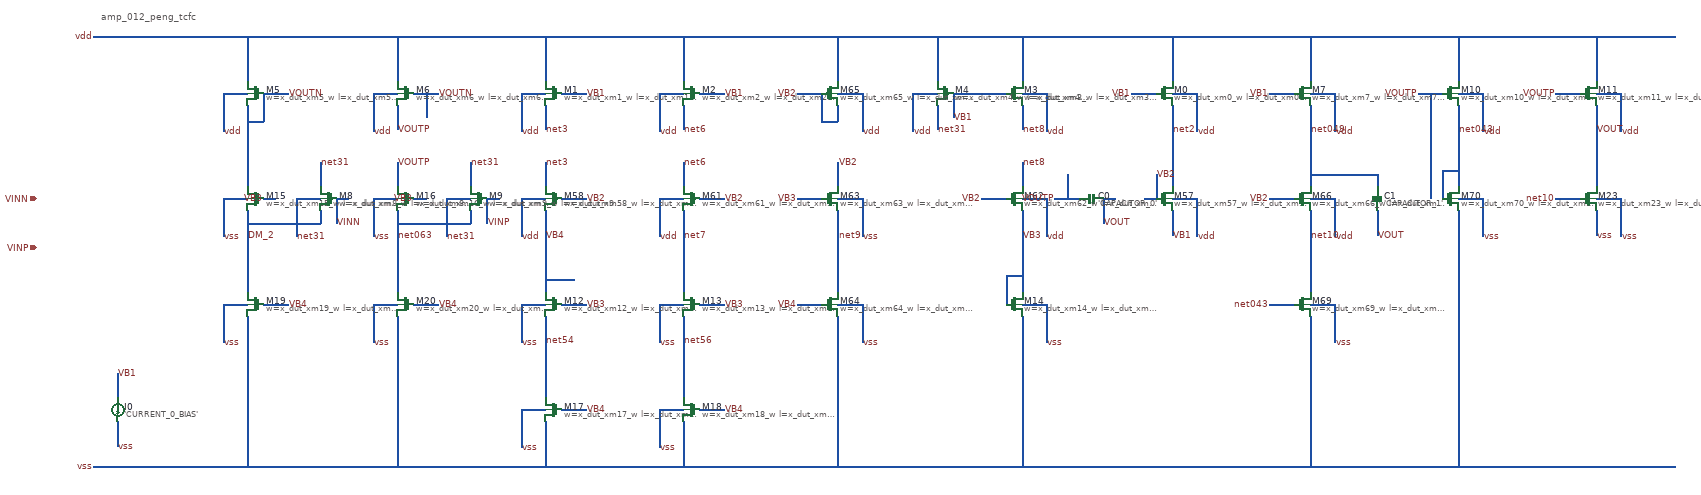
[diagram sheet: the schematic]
v {xschem version=3.4.6 file_version=1.2}
G {}
K {}
V {}
S {}
E {}
T {amp_012_peng_tcfc} -1910 -200 0 0 0.4 0.4 {}
C {devices/capa_np.sym} 530 260 1 0 {name=C0 value='CAPACITOR_0'}
C {devices/capa_np.sym} 1235 260 0 0 {name=C1 value='CAPACITOR_1'}
C {devices/isource_np.sym} -1870 780 0 0 {name=I0 value='CURRENT_0_BIAS'}
C {devices/sg13_lv_pmos_np.sym} 710 0 0 0 {name=M0 model=sg13_lv_pmos spiceprefix=X w=x_dut_xm0_w l=x_dut_xm0_l m=x_dut_xm0_m}
C {devices/sg13_lv_pmos_np.sym} -795 0 0 1 {name=M1 model=sg13_lv_pmos spiceprefix=X w=x_dut_xm1_w l=x_dut_xm1_l m=x_dut_xm1_m}
C {devices/sg13_lv_pmos_np.sym} 1415 0 0 0 {name=M10 model=sg13_lv_pmos spiceprefix=X w=x_dut_xm10_w l=x_dut_xm10_l m=x_dut_xm10_m}
C {devices/sg13_lv_pmos_np.sym} 1755 0 0 0 {name=M11 model=sg13_lv_pmos spiceprefix=X w=x_dut_xm11_w l=x_dut_xm11_l m=x_dut_xm11_m}
C {devices/sg13_lv_nmos_np.sym} -795 520 0 1 {name=M12 model=sg13_lv_nmos spiceprefix=X w=x_dut_xm12_w l=x_dut_xm12_l m=x_dut_xm12_m}
C {devices/sg13_lv_nmos_np.sym} -455 520 0 1 {name=M13 model=sg13_lv_nmos spiceprefix=X w=x_dut_xm13_w l=x_dut_xm13_l m=x_dut_xm13_m}
C {devices/sg13_lv_nmos_np.sym} 340 520 0 0 {name=M14 model=sg13_lv_nmos spiceprefix=X w=x_dut_xm14_w l=x_dut_xm14_l m=x_dut_xm14_m}
C {devices/sg13_lv_nmos_np.sym} -1530 260 0 1 {name=M15 model=sg13_lv_nmos spiceprefix=X w=x_dut_xm15_w l=x_dut_xm15_l m=x_dut_xm15_m}
C {devices/sg13_lv_nmos_np.sym} -1160 260 0 1 {name=M16 model=sg13_lv_nmos spiceprefix=X w=x_dut_xm16_w l=x_dut_xm16_l m=x_dut_xm16_m}
C {devices/sg13_lv_nmos_np.sym} -795 780 0 1 {name=M17 model=sg13_lv_nmos spiceprefix=X w=x_dut_xm17_w l=x_dut_xm17_l m=x_dut_xm17_m}
C {devices/sg13_lv_nmos_np.sym} -455 780 0 1 {name=M18 model=sg13_lv_nmos spiceprefix=X w=x_dut_xm18_w l=x_dut_xm18_l m=x_dut_xm18_m}
C {devices/sg13_lv_nmos_np.sym} -1530 520 0 1 {name=M19 model=sg13_lv_nmos spiceprefix=X w=x_dut_xm19_w l=x_dut_xm19_l m=x_dut_xm19_m}
C {devices/sg13_lv_pmos_np.sym} -455 0 0 1 {name=M2 model=sg13_lv_pmos spiceprefix=X w=x_dut_xm2_w l=x_dut_xm2_l m=x_dut_xm2_m}
C {devices/sg13_lv_nmos_np.sym} -1160 520 0 1 {name=M20 model=sg13_lv_nmos spiceprefix=X w=x_dut_xm20_w l=x_dut_xm20_l m=x_dut_xm20_m}
C {devices/sg13_lv_nmos_np.sym} 1755 260 0 0 {name=M23 model=sg13_lv_nmos spiceprefix=X w=x_dut_xm23_w l=x_dut_xm23_l m=x_dut_xm23_m}
C {devices/sg13_lv_pmos_np.sym} 340 0 0 0 {name=M3 model=sg13_lv_pmos spiceprefix=X w=x_dut_xm3_w l=x_dut_xm3_l m=x_dut_xm3_m}
C {devices/sg13_lv_pmos_np.sym} 170 0 0 1 {name=M4 model=sg13_lv_pmos spiceprefix=X w=x_dut_xm4_w l=x_dut_xm4_l m=x_dut_xm4_m}
C {devices/sg13_lv_pmos_np.sym} -1530 0 0 1 {name=M5 model=sg13_lv_pmos spiceprefix=X w=x_dut_xm5_w l=x_dut_xm5_l m=x_dut_xm5_m}
C {devices/sg13_lv_pmos_np.sym} 710 260 0 0 {name=M57 model=sg13_lv_pmos spiceprefix=X w=x_dut_xm57_w l=x_dut_xm57_l m=x_dut_xm57_m}
C {devices/sg13_lv_pmos_np.sym} -795 260 0 1 {name=M58 model=sg13_lv_pmos spiceprefix=X w=x_dut_xm58_w l=x_dut_xm58_l m=x_dut_xm58_m}
C {devices/sg13_lv_pmos_np.sym} -1160 0 0 1 {name=M6 model=sg13_lv_pmos spiceprefix=X w=x_dut_xm6_w l=x_dut_xm6_l m=x_dut_xm6_m}
C {devices/sg13_lv_pmos_np.sym} -455 260 0 1 {name=M61 model=sg13_lv_pmos spiceprefix=X w=x_dut_xm61_w l=x_dut_xm61_l m=x_dut_xm61_m}
C {devices/sg13_lv_pmos_np.sym} 340 260 0 0 {name=M62 model=sg13_lv_pmos spiceprefix=X w=x_dut_xm62_w l=x_dut_xm62_l m=x_dut_xm62_m}
C {devices/sg13_lv_nmos_np.sym} -115 260 0 0 {name=M63 model=sg13_lv_nmos spiceprefix=X w=x_dut_xm63_w l=x_dut_xm63_l m=x_dut_xm63_m}
C {devices/sg13_lv_nmos_np.sym} -115 520 0 0 {name=M64 model=sg13_lv_nmos spiceprefix=X w=x_dut_xm64_w l=x_dut_xm64_l m=x_dut_xm64_m}
C {devices/sg13_lv_pmos_np.sym} -115 0 0 0 {name=M65 model=sg13_lv_pmos spiceprefix=X w=x_dut_xm65_w l=x_dut_xm65_l m=x_dut_xm65_m}
C {devices/sg13_lv_pmos_np.sym} 1050 260 0 0 {name=M66 model=sg13_lv_pmos spiceprefix=X w=x_dut_xm66_w l=x_dut_xm66_l m=x_dut_xm66_m}
C {devices/sg13_lv_nmos_np.sym} 1050 520 0 0 {name=M69 model=sg13_lv_nmos spiceprefix=X w=x_dut_xm69_w l=x_dut_xm69_l m=x_dut_xm69_m}
C {devices/sg13_lv_pmos_np.sym} 1050 0 0 0 {name=M7 model=sg13_lv_pmos spiceprefix=X w=x_dut_xm7_w l=x_dut_xm7_l m=x_dut_xm7_m}
C {devices/sg13_lv_nmos_np.sym} 1415 260 0 0 {name=M70 model=sg13_lv_nmos spiceprefix=X w=x_dut_xm70_w l=x_dut_xm70_l m=x_dut_xm70_m}
C {devices/sg13_lv_pmos_np.sym} -1350 260 0 1 {name=M8 model=sg13_lv_pmos spiceprefix=X w=x_dut_xm8_w l=x_dut_xm8_l m=x_dut_xm8_m}
C {devices/sg13_lv_pmos_np.sym} -980 260 0 1 {name=M9 model=sg13_lv_pmos spiceprefix=X w=x_dut_xm9_w l=x_dut_xm9_l m=x_dut_xm9_m}
N -1870 690 -1870 750 {}
N -1870 810 -1870 870 {}
N -1610 0 -1610 94 {}
N -1610 260 -1610 354 {}
N -1610 520 -1610 614 {}
N -1550 -140 -1550 -30 {}
N -1550 30 -1550 230 {}
N -1550 290 -1550 490 {}
N -1550 550 -1550 920 {}
N -1510 0 -1510 70 {}
N -1430 260 -1430 354 {}
N -1370 170 -1370 230 {}
N -1370 290 -1370 320 {}
N -1330 260 -1330 320 {}
N -1240 0 -1240 94 {}
N -1240 260 -1240 354 {}
N -1240 520 -1240 614 {}
N -1180 -140 -1180 -30 {}
N -1180 30 -1180 90 {}
N -1180 170 -1180 230 {}
N -1180 290 -1180 490 {}
N -1180 550 -1180 920 {}
N -1110 0 -1110 60 {}
N -1060 260 -1060 354 {}
N -1000 170 -1000 230 {}
N -1000 290 -1000 320 {}
N -960 260 -960 320 {}
N -875 0 -875 94 {}
N -875 260 -875 354 {}
N -875 520 -875 614 {}
N -875 780 -875 874 {}
N -815 -140 -815 -30 {}
N -815 30 -815 90 {}
N -815 170 -815 230 {}
N -815 290 -815 490 {}
N -815 550 -815 750 {}
N -815 810 -815 920 {}
N -535 0 -535 94 {}
N -535 260 -535 354 {}
N -535 520 -535 614 {}
N -535 780 -535 874 {}
N -475 -140 -475 -30 {}
N -475 30 -475 90 {}
N -475 170 -475 230 {}
N -475 290 -475 490 {}
N -475 550 -475 750 {}
N -475 810 -475 920 {}
N -135 0 -135 70 {}
N -95 -140 -95 -30 {}
N -95 30 -95 70 {}
N -95 170 -95 230 {}
N -95 290 -95 490 {}
N -95 550 -95 920 {}
N -35 0 -35 94 {}
N -35 260 -35 354 {}
N -35 520 -35 614 {}
N 90 0 90 94 {}
N 150 -140 150 -30 {}
N 150 30 150 90 {}
N 190 0 190 60 {}
N 320 450 320 520 {}
N 360 -140 360 -30 {}
N 360 30 360 90 {}
N 360 170 360 230 {}
N 360 290 360 490 {}
N 360 550 360 920 {}
N 420 0 420 94 {}
N 420 260 420 354 {}
N 420 520 420 614 {}
N 470 200 470 260 {}
N 560 260 560 320 {}
N 690 200 690 260 {}
N 730 -140 730 -30 {}
N 730 30 730 230 {}
N 730 290 730 350 {}
N 790 0 790 94 {}
N 790 260 790 354 {}
N 1070 -140 1070 -30 {}
N 1070 30 1070 230 {}
N 1070 290 1070 490 {}
N 1070 550 1070 920 {}
N 1130 0 1130 94 {}
N 1130 260 1130 354 {}
N 1130 520 1130 614 {}
N 1235 200 1235 230 {}
N 1235 290 1235 350 {}
N 1365 0 1365 260 {}
N 1395 190 1395 260 {}
N 1435 -140 1435 -30 {}
N 1435 30 1435 230 {}
N 1435 290 1435 920 {}
N 1495 0 1495 94 {}
N 1495 260 1495 354 {}
N 1775 -140 1775 -30 {}
N 1775 30 1775 230 {}
N 1775 290 1775 350 {}
N 1835 0 1835 94 {}
N 1835 260 1835 354 {}
N -1930 -140 1970 -140 {}
N -1610 0 -1550 0 {}
N -1510 0 -1450 0 {}
N -1240 0 -1180 0 {}
N -1140 0 -1080 0 {}
N -875 0 -815 0 {}
N -775 0 -715 0 {}
N -535 0 -475 0 {}
N -435 0 -375 0 {}
N -195 0 -135 0 {}
N -95 0 -35 0 {}
N 90 0 150 0 {}
N 190 0 320 0 {}
N 360 0 420 0 {}
N 630 0 690 0 {}
N 730 0 790 0 {}
N 970 0 1030 0 {}
N 1070 0 1130 0 {}
N 1335 0 1395 0 {}
N 1435 0 1495 0 {}
N 1675 0 1735 0 {}
N 1775 0 1835 0 {}
N -1550 70 -1510 70 {}
N -135 70 -95 70 {}
N 1395 190 1435 190 {}
N 1070 200 1235 200 {}
N -1610 260 -1550 260 {}
N -1510 260 -1480 260 {}
N -1430 260 -1370 260 {}
N -1330 260 -1300 260 {}
N -1240 260 -1180 260 {}
N -1140 260 -1110 260 {}
N -1060 260 -1000 260 {}
N -960 260 -930 260 {}
N -875 260 -815 260 {}
N -775 260 -715 260 {}
N -535 260 -475 260 {}
N -435 260 -375 260 {}
N -195 260 -135 260 {}
N -95 260 -35 260 {}
N 260 260 320 260 {}
N 360 260 420 260 {}
N 440 260 500 260 {}
N 560 260 590 260 {}
N 660 260 690 260 {}
N 730 260 790 260 {}
N 970 260 1030 260 {}
N 1070 260 1130 260 {}
N 1435 260 1495 260 {}
N 1675 260 1735 260 {}
N 1775 260 1835 260 {}
N -1550 320 -1370 320 {}
N -1180 320 -1000 320 {}
N 320 450 360 450 {}
N -815 460 -745 460 {}
N -1610 520 -1550 520 {}
N -1510 520 -1450 520 {}
N -1240 520 -1180 520 {}
N -1140 520 -1080 520 {}
N -875 520 -815 520 {}
N -775 520 -715 520 {}
N -535 520 -475 520 {}
N -435 520 -375 520 {}
N -195 520 -135 520 {}
N -95 520 -35 520 {}
N 360 520 420 520 {}
N 970 520 1030 520 {}
N 1070 520 1130 520 {}
N -875 780 -815 780 {}
N -775 780 -715 780 {}
N -535 780 -475 780 {}
N -435 780 -375 780 {}
N -1930 920 1970 920 {}
C {devices/lab_wire.sym} -1930 -140 0 0 {name=l0 lab=vdd}
C {devices/lab_wire.sym} -1930 920 0 0 {name=l1 lab=vss}
C {devices/lab_wire.sym} -1550 350 2 0 {name=l2 lab=DM_2}
C {devices/lab_wire.sym} -715 0 0 1 {name=l3 lab=VB1}
C {devices/lab_wire.sym} -375 0 0 1 {name=l4 lab=VB1}
C {devices/lab_wire.sym} 190 60 2 0 {name=l5 lab=VB1}
C {devices/lab_wire.sym} 630 0 0 0 {name=l6 lab=VB1}
C {devices/lab_wire.sym} 730 350 2 0 {name=l7 lab=VB1}
C {devices/lab_wire.sym} 970 0 0 0 {name=l8 lab=VB1}
C {devices/lab_wire.sym} -715 260 0 1 {name=l9 lab=VB2}
C {devices/lab_wire.sym} -375 260 0 1 {name=l10 lab=VB2}
C {devices/lab_wire.sym} -195 0 0 0 {name=l11 lab=VB2}
C {devices/lab_wire.sym} -95 170 0 1 {name=l12 lab=VB2}
C {devices/lab_wire.sym} 260 260 0 0 {name=l13 lab=VB2}
C {devices/lab_wire.sym} 690 200 0 1 {name=l14 lab=VB2}
C {devices/lab_wire.sym} 970 260 0 0 {name=l15 lab=VB2}
C {devices/lab_wire.sym} -1510 260 0 0 {name=l16 lab=VB3}
C {devices/lab_wire.sym} -1140 260 0 0 {name=l17 lab=VB3}
C {devices/lab_wire.sym} -715 520 0 1 {name=l18 lab=VB3}
C {devices/lab_wire.sym} -375 520 0 1 {name=l19 lab=VB3}
C {devices/lab_wire.sym} -195 260 0 0 {name=l20 lab=VB3}
C {devices/lab_wire.sym} 360 350 2 0 {name=l21 lab=VB3}
C {devices/lab_wire.sym} -1450 520 0 1 {name=l22 lab=VB4}
C {devices/lab_wire.sym} -1080 520 0 1 {name=l23 lab=VB4}
C {devices/lab_wire.sym} -815 350 2 0 {name=l24 lab=VB4}
C {devices/lab_wire.sym} -715 780 0 1 {name=l25 lab=VB4}
C {devices/lab_wire.sym} -375 780 0 1 {name=l26 lab=VB4}
C {devices/lab_wire.sym} -195 520 0 0 {name=l27 lab=VB4}
C {devices/lab_wire.sym} -1330 320 2 0 {name=l28 lab=VINN}
C {devices/lab_wire.sym} -960 320 2 0 {name=l29 lab=VINP}
C {devices/lab_wire.sym} 560 320 2 0 {name=l30 lab=VOUT}
C {devices/lab_wire.sym} 1235 350 2 0 {name=l31 lab=VOUT}
C {devices/lab_wire.sym} 1775 90 2 0 {name=l32 lab=VOUT}
C {devices/lab_wire.sym} -1450 0 0 1 {name=l33 lab=VOUTN}
C {devices/lab_wire.sym} -1080 0 0 1 {name=l34 lab=VOUTN}
C {devices/lab_wire.sym} -1180 90 2 0 {name=l35 lab=VOUTP}
C {devices/lab_wire.sym} -1180 170 0 1 {name=l36 lab=VOUTP}
C {devices/lab_wire.sym} 440 260 0 0 {name=l37 lab=VOUTP}
C {devices/lab_wire.sym} 1335 0 0 0 {name=l38 lab=VOUTP}
C {devices/lab_wire.sym} 1675 0 0 0 {name=l39 lab=VOUTP}
C {devices/lab_wire.sym} 970 520 0 0 {name=l40 lab=net043}
C {devices/lab_wire.sym} 1435 90 2 0 {name=l41 lab=net043}
C {devices/lab_wire.sym} 1070 90 2 0 {name=l42 lab=net049}
C {devices/lab_wire.sym} -1180 350 2 0 {name=l43 lab=net063}
C {devices/lab_wire.sym} 1070 350 2 0 {name=l44 lab=net10}
C {devices/lab_wire.sym} 1675 260 0 0 {name=l45 lab=net10}
C {devices/lab_wire.sym} 730 90 2 0 {name=l46 lab=net2}
C {devices/lab_wire.sym} -815 90 2 0 {name=l47 lab=net3}
C {devices/lab_wire.sym} -815 170 0 1 {name=l48 lab=net3}
C {devices/lab_wire.sym} -1370 170 0 1 {name=l49 lab=net31}
C {devices/lab_wire.sym} -1000 170 0 1 {name=l50 lab=net31}
C {devices/lab_wire.sym} 150 90 2 0 {name=l51 lab=net31}
C {devices/lab_wire.sym} -815 610 2 0 {name=l52 lab=net54}
C {devices/lab_wire.sym} -475 610 2 0 {name=l53 lab=net56}
C {devices/lab_wire.sym} -475 90 2 0 {name=l54 lab=net6}
C {devices/lab_wire.sym} -475 170 0 1 {name=l55 lab=net6}
C {devices/lab_wire.sym} -475 350 2 0 {name=l56 lab=net7}
C {devices/lab_wire.sym} 360 90 2 0 {name=l57 lab=net8}
C {devices/lab_wire.sym} 360 170 0 1 {name=l58 lab=net8}
C {devices/lab_wire.sym} -95 350 2 0 {name=l59 lab=net9}
C {devices/lab_wire.sym} -1430 354 2 0 {name=l60 lab=net31}
C {devices/lab_wire.sym} -1060 354 2 0 {name=l61 lab=net31}
C {devices/lab_wire.sym} 790 94 2 0 {name=l62 lab=vdd}
C {devices/lab_wire.sym} -875 94 2 0 {name=l63 lab=vdd}
C {devices/lab_wire.sym} 1495 94 2 0 {name=l64 lab=vdd}
C {devices/lab_wire.sym} 1835 94 2 0 {name=l65 lab=vdd}
C {devices/lab_wire.sym} -535 94 2 0 {name=l66 lab=vdd}
C {devices/lab_wire.sym} 420 94 2 0 {name=l67 lab=vdd}
C {devices/lab_wire.sym} 90 94 2 0 {name=l68 lab=vdd}
C {devices/lab_wire.sym} -1610 94 2 0 {name=l69 lab=vdd}
C {devices/lab_wire.sym} 790 354 2 0 {name=l70 lab=vdd}
C {devices/lab_wire.sym} -875 354 2 0 {name=l71 lab=vdd}
C {devices/lab_wire.sym} -1240 94 2 0 {name=l72 lab=vdd}
C {devices/lab_wire.sym} -535 354 2 0 {name=l73 lab=vdd}
C {devices/lab_wire.sym} 420 354 2 0 {name=l74 lab=vdd}
C {devices/lab_wire.sym} -35 94 2 0 {name=l75 lab=vdd}
C {devices/lab_wire.sym} 1130 354 2 0 {name=l76 lab=vdd}
C {devices/lab_wire.sym} 1130 94 2 0 {name=l77 lab=vdd}
C {devices/lab_wire.sym} -875 614 2 0 {name=l78 lab=vss}
C {devices/lab_wire.sym} -535 614 2 0 {name=l79 lab=vss}
C {devices/lab_wire.sym} 420 614 2 0 {name=l80 lab=vss}
C {devices/lab_wire.sym} -1610 354 2 0 {name=l81 lab=vss}
C {devices/lab_wire.sym} -1240 354 2 0 {name=l82 lab=vss}
C {devices/lab_wire.sym} -875 874 2 0 {name=l83 lab=vss}
C {devices/lab_wire.sym} -535 874 2 0 {name=l84 lab=vss}
C {devices/lab_wire.sym} -1610 614 2 0 {name=l85 lab=vss}
C {devices/lab_wire.sym} -1240 614 2 0 {name=l86 lab=vss}
C {devices/lab_wire.sym} 1835 354 2 0 {name=l87 lab=vss}
C {devices/lab_wire.sym} -35 354 2 0 {name=l88 lab=vss}
C {devices/lab_wire.sym} -35 614 2 0 {name=l89 lab=vss}
C {devices/lab_wire.sym} 1130 614 2 0 {name=l90 lab=vss}
C {devices/lab_wire.sym} 1495 354 2 0 {name=l91 lab=vss}
C {devices/lab_wire.sym} -1870 690 0 1 {name=l92 lab=VB1}
C {devices/lab_wire.sym} -1870 870 2 0 {name=l93 lab=vss}
C {devices/lab_wire.sym} 1775 350 2 0 {name=l94 lab=vss}
C {devices/ipin.sym} -2070 260 0 0 {name=p0 lab=VINN}
C {devices/ipin.sym} -2070 380 0 0 {name=p1 lab=VINP}
